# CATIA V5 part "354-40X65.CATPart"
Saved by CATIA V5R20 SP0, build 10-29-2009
Part number: 354-40X65
Definition: NONE
Nomenclature: 354-40X65
Source: Unknown
Description: 354-40X65
Bounding box of the stored display mesh (mm): x -33 to 32, y -26 to 26, z -26 to 26
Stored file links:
  C:\Users\Utente\Desktop\IO LAVORO\3D X SITO CF\X SITO\PLASTICA\354\354-40X65.CATPart

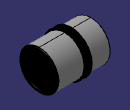
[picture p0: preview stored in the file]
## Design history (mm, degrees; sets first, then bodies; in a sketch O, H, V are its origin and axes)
Body1 "354-40X65" (main body)
  Solid1: solid without history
